VERSION 5.7 ;
  NOWIREEXTENSIONATPIN ON ;
  DIVIDERCHAR "/" ;
  BUSBITCHARS "[]" ;
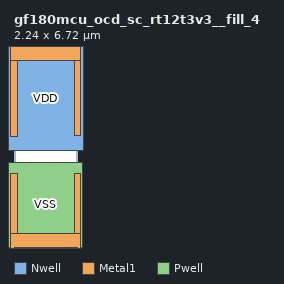
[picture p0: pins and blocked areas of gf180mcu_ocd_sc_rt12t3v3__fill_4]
MACRO gf180mcu_ocd_sc_rt12t3v3__fill_4
  CLASS CORE SPACER ;
  FOREIGN gf180mcu_ocd_sc_rt12t3v3__fill_4 ;
  ORIGIN 0.000 0.000 ;
  SIZE 2.240 BY 6.720 ;
  SYMMETRY X Y ;
  SITE unithd ;
  PIN VDD
    DIRECTION INOUT ;
    USE POWER ;
    SHAPE ABUTMENT ;
    PORT
      LAYER Nwell ;
        RECT -0.610 3.245 2.850 7.330 ;
      LAYER Metal1 ;
        RECT -0.115 6.420 2.355 7.020 ;
        RECT -0.115 3.745 0.115 6.420 ;
        RECT 2.125 3.750 2.355 6.420 ;
    END
  END VDD
  PIN VSS
    DIRECTION INOUT ;
    USE GROUND ;
    SHAPE ABUTMENT ;
    PORT
      LAYER Pwell ;
        RECT -0.180 -0.180 2.420 2.815 ;
        RECT 0.000 -0.300 2.240 -0.180 ;
      LAYER Metal1 ;
        RECT -0.115 0.300 0.115 2.410 ;
        RECT 2.125 0.300 2.355 2.410 ;
        RECT -0.115 -0.300 2.355 0.300 ;
    END
  END VSS
END gf180mcu_ocd_sc_rt12t3v3__fill_4
END LIBRARY

